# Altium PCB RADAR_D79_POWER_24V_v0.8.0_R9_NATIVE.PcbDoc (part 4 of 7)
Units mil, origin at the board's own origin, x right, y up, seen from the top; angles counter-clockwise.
Board outline 3110.24 x 3110.24 mil, 8 copper layers (Top Layer, GND1, SIG1, PWR1, PWR2, SIG2, GND2, Bottom Layer), stack 55.2 mil thick; 304 components, 269 nets, 1408 pads, 1366 vias.

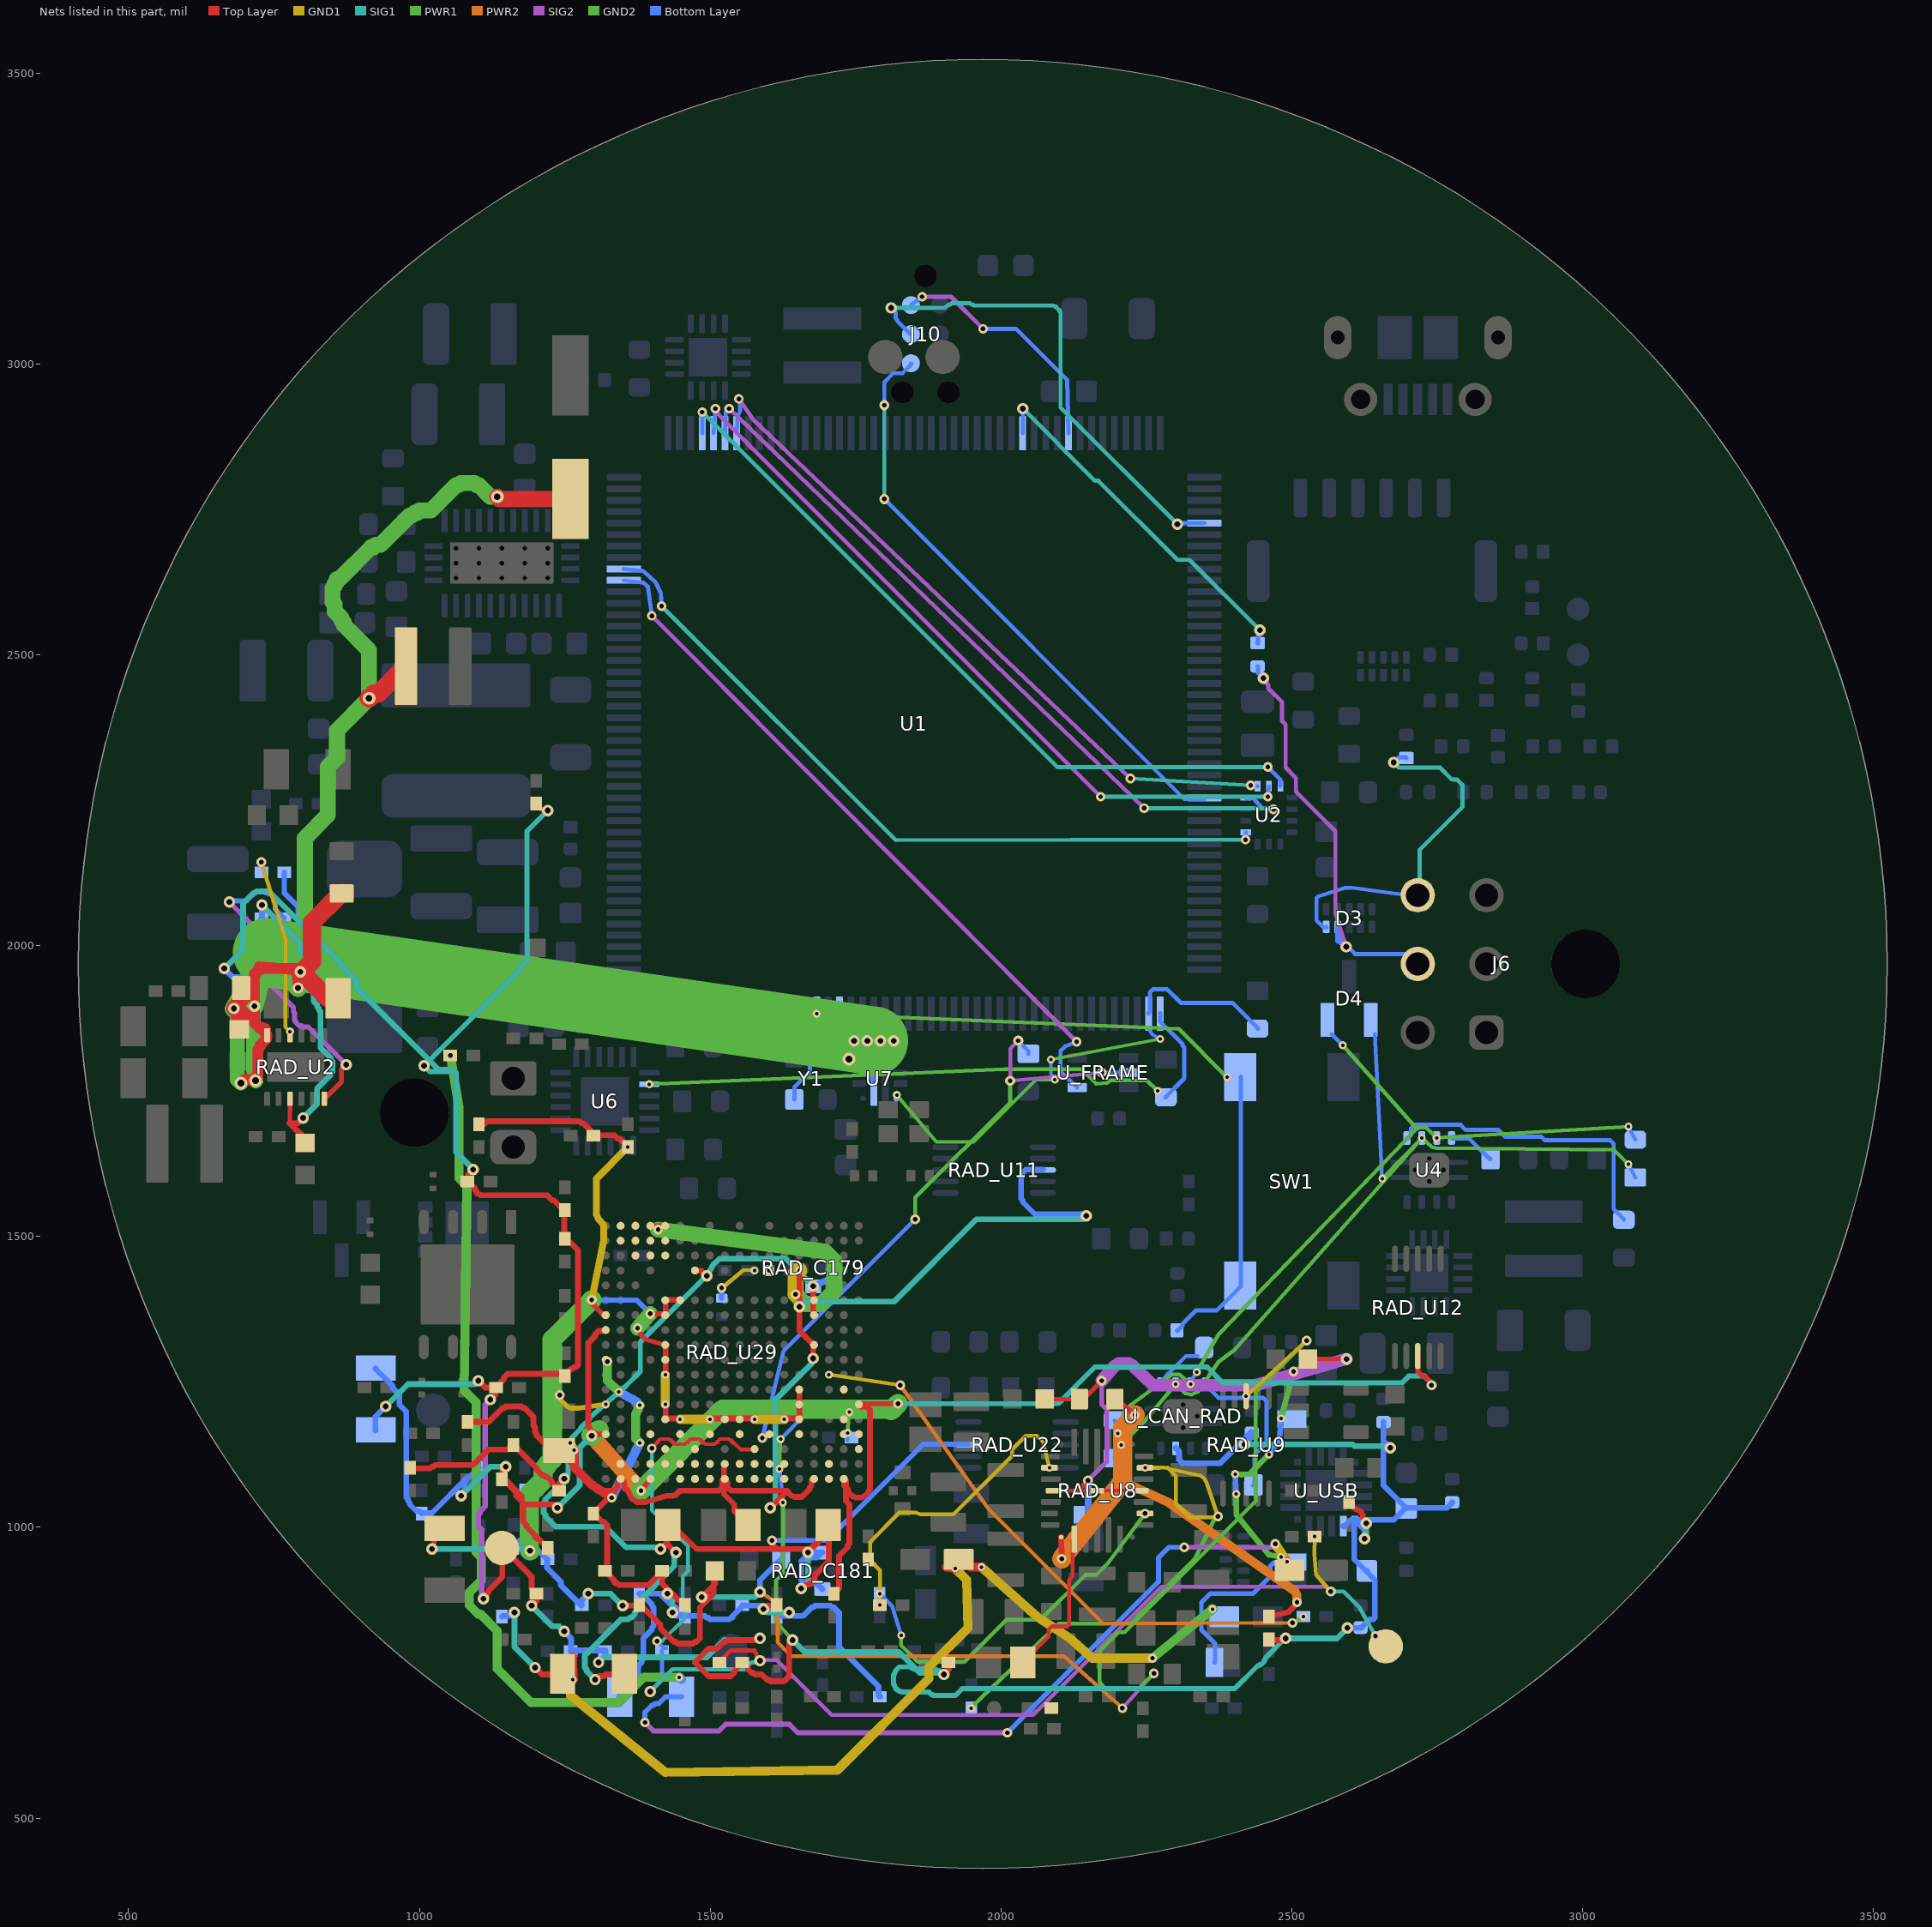
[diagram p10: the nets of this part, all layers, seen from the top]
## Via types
v1: diameter 13.77, hole 5.9, Top Layer to GND1, tented both sides, 393 vias
v2: diameter 16.54, hole 7.87, Top Layer to Bottom Layer, tented both sides, 129 vias
v3: diameter 13.77/13.77 (per signal layer), hole 5.9, Top Layer to GND1, tented both sides, 120 vias
v4: diameter 13.77, hole 5.9, Top Layer to GND1, tented top, 104 vias
v5: diameter 19.68, hole 9.84, Top Layer to Bottom Layer, 103 vias
v6: diameter 19.68, hole 9.84, Top Layer to Bottom Layer, tented both sides, 93 vias
v7: diameter 13.78, hole 5.91, Top Layer to GND1, tented both sides, 83 vias
v8: diameter 17.32, hole 7.87, Top Layer to Bottom Layer, tented both sides, 69 vias
v9: diameter 13.78, hole 5.91, GND2 to Bottom Layer, tented both sides, 68 vias
v10: diameter 13.78, hole 5.91, Top Layer to GND1, tented bottom, 55 vias
v11: diameter 13.78, hole 5.91, GND2 to Bottom Layer, tented top, 43 vias
v12: diameter 16.54, hole 7.87, GND2 to Bottom Layer, tented both sides, 22 vias
v13: diameter 22.05, hole 11.81, Top Layer to Bottom Layer, tented both sides, 17 vias
v14: diameter 16.54, hole 7.87, Top Layer to Bottom Layer, 14 vias
v15: diameter 18.11, hole 9.06, Top Layer to Bottom Layer, 7 vias
v16: diameter 22.83, hole 11.81, Top Layer to Bottom Layer, 6 vias
v17: diameter 22.05, hole 11.81, Top Layer to Bottom Layer, 6 vias
v18: diameter 22.83, hole 11.81, Top Layer to Bottom Layer, tented both sides, 5 vias
v19: diameter 19.68, hole 7.87, Top Layer to Bottom Layer, 3 vias
v20: diameter 17.32, hole 8.66, Top Layer to Bottom Layer, 3 vias
v21: diameter 20.47, hole 9.84, Top Layer to Bottom Layer, 3 vias
v22: diameter 17.72, hole 9.84, Top Layer to Bottom Layer, tented both sides, 2 vias
v23: diameter 22.05, hole 11.02, Top Layer to Bottom Layer, 2 vias
v24: diameter 19.68, hole 11.81, Top Layer to Bottom Layer, 2 vias
v25: diameter 19.68, hole 9.84, SIG1 to Bottom Layer, 2 vias
v26: diameter 16.54, hole 7.87, SIG1 to SIG2, tented both sides, 2 vias
v27: diameter 16.54, hole 7.87, Top Layer to SIG1, 2 vias
v28: diameter 13.78, hole 5.91, Top Layer to GND1, 2 vias
v29: diameter 18, hole 9.84, Top Layer to Bottom Layer, tented both sides, 1 vias
v30: diameter 18.11, hole 9.06, Top Layer to Bottom Layer, tented both sides, 1 vias
v31: diameter 19.68, hole 9.84, GND2 to Bottom Layer, tented both sides, 1 vias
v32: diameter 17.32, hole 7.87, SIG1 to Bottom Layer, tented both sides, 1 vias
v33: diameter 19.68, hole 9.84, SIG2 to Bottom Layer, 1 vias
v34: diameter 16.54, hole 7.87, GND1 to PWR2, tented both sides, 1 vias

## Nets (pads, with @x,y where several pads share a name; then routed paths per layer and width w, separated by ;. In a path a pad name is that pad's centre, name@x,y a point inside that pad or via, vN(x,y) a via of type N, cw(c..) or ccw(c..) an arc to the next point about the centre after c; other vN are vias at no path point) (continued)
HOST_UART2_RX_EXT: D3.5 J6.6 R604.1 | length 624.9
  SIG1 w7.09: v5(2675.2,2314.96) 2684.06,2306.1 2754.92,2306.1 2775.59,2285.43 2784.45,2285.43 2793.31,2276.57 2793.31,2238.19 2719.49,2164.37 2719.49,2090.55 2716.54,2087.6 J6.6@2716.54,2086.61
  Bottom Layer w7.09: D3.5@2559.06,2032.09 2560.04,2031.5 2554.13,2031.5 2542.32,2043.31 2542.32,2081.69 2545.28,2084.65 2591.54,2099.41 2604.33,2099.41 2713.58,2084.65 2716.54,2087.6 J6.6@2716.54,2086.61 ; v5(2675.2,2314.96) 2684.06,2323.82 2695.87,2323.82 R604.1@2696.85,2322.44
HOST_UART2_TX: R603.2 U1.120 | length 634.1
  SIG1 w7.09: v6(2037.4,2923.23) 2161.42,2799.21 2167.32,2799.21 2303.15,2663.39 2323.82,2663.39 v5(2444.88,2542.32)
  Bottom Layer w7.09: U1.120@2037.4,2880.91 2037.4,2881.89 v6(2037.4,2923.23) ; R603.2@2440.94,2520.08 2441.93,2518.7 2441.93,2539.37 v5(2444.88,2542.32)
HOST_UART2_TX_EXT: D3.4 J6.5 R603.1 | length 758.4
  SIG2 w7.09: v5(2450.79,2459.65) 2456.69,2453.74 2456.69,2450.79 2459.65,2447.83 2459.65,2441.93 2483.27,2418.31 2483.27,2385.83 2489.17,2379.92 2489.17,2306.1 2506.89,2288.39 2506.89,2264.76 2574.8,2196.85 2574.8,2055.12 v33(2593.5,1998.03)
  Bottom Layer w7.09: R603.1@2440.94,2479.92 2441.93,2480.32 2441.93,2468.5 v5(2450.79,2459.65) ; D3.4@2578.74,2032.09 D3.4@2577.76,2031.5 ; v33(2593.5,1998.03) 2577.76,2007.87 D3.4@2577.76,2031.5 ; J6.5@2716.54,1968.5 2715.94,1969.09 2699.41,1985.63 2608.46,1985.63 2580.91,2013.19 2580.71,2013.78 2580.71,2028.54 D3.4@2577.76,2031.5
IMU_DRDY: U1.80 U2.4 | length 1289
  SIG1 w7.09: v2(1416.34,2583.66) 1818.9,2181.1 v2(2420.28,2182.09)
  Bottom Layer w7.09: U1.80@1351.38,2647.64 1381.89,2644.68 1386.81,2642.72 1406.5,2624.02 1415.35,2605.32 v2(1416.34,2583.66) ; v2(2420.28,2182.09) U2.4@2420.77,2194.88
IMU_MISO: U1.94 U2.1 | length 1314.4
  SIG1 w7.09: v26(2246.06,2236.22) 2466.54,2236.22 v2(2468.5,2234.25)
  SIG2 w7.09: v2(1532.48,2923.23) v26(2246.06,2236.22)
  Bottom Layer w7.09: U1.94@1525.59,2880.91 1526.57,2917.32 v2(1532.48,2923.23) ; U2.1@2420.77,2253.94 2433.07,2253.94 2448.82,2236.22 v2(2468.5,2234.25)
IMU_MOSI: U1.95 U2.14 | length 1218.4
  SIG1 w7.09: v26(2222.44,2287.4) v2(2429.13,2275.59)
  SIG2 w7.09: v2(1549.21,2939.96) 1574.8,2903.54 v26(2222.44,2287.4)
  Bottom Layer w7.09: U1.95@1545.28,2880.91 1547.24,2911.42 1550.2,2915.35 1551.18,2918.31 1551.18,2937.99 v2(1549.21,2939.96) ; v2(2429.13,2275.59) U2.14@2440.94,2274.11
IMU_NSS: U1.92 U2.12 | length 1303.6
  SIG1 w7.09: v2(1486.22,2917.32) 2096.46,2307.09 v2(2458.66,2307.09)
  Bottom Layer w7.09: U1.92@1486.22,2880.91 v2(1486.22,2917.32) ; v2(2458.66,2307.09) 2480.32,2285.43 U2.12@2480.31,2274.11
IMU_SCK: U1.93 U2.13 | length 1289
  SIG1 w7.09: v2(2171.26,2255.91) v2(2458.66,2255.91)
  SIG2 w7.09: v2(1508.86,2923.23) 1513.78,2913.39 v2(2171.26,2255.91)
  Bottom Layer w7.09: U1.93@1505.91,2880.91 v2(1508.86,2923.23) ; v2(2458.66,2255.91) U2.13@2460.63,2274.11
MCU_HSE_25M: U1.29 Y1.3 | length 204.3
  Bottom Layer w7.09: Y1.3@1644.68,1735.24 1644.68,1736.22 1644.68,1756.89 1668.31,1780.51 1671.26,1780.51 1671.26,1830.71 1683.07,1842.52 1718.5,1842.52 1718.5,1845.47 1721.46,1848.43 1721.46,1883.86 U1.29@1722.44,1882.87
NRST: C115.1 SW1.1 U1.31 | length 1247.5
  GND2 w6.69: v11(1683.07,1882.87) 2305.51,1856.69 v11(2388.58,1773.62)
  Bottom Layer w7.09: C115.1@2302.36,1338.58 2303.15,1337.6 2312.01,1346.46 2312.01,1349.41 2335.63,1373.03 2371.06,1373.03 SW1.1@2412.4,1414.37 ; SW1.1@2411.42,1415.35 SW1.1@2412.4,1414.37 ; SW1.1@2411.42,1773.62 2412.4,1774.61 SW1.1@2412.4,1414.37
RAD_CAN_SHDN: R_CAN_SHDN.1 U_CAN_RAD.5 | length 81.7
  Bottom Layer w6.3: U_CAN_RAD.5@2276.18,1253.35 2276.08,1253.69 2277.31,1253.69 2285.93,1262.3 2285.93,1263.53 2287.16,1263.53 2287.16,1264.76 2288.39,1264.76 2288.39,1265.99 2289.62,1265.99 2317.91,1294.29 2337.6,1294.29 R_CAN_SHDN.1@2338.19,1294.88
RAD_CAN_STB: R_CAN_STB.1 U_CAN_RAD.8 | length 275.4
  Bottom Layer w7.09: U_CAN_RAD.8@2351.38,1246.06 2350.39,1246.06 2374.02,1222.44 2450.79,1222.44 2456.69,1216.54 2456.69,1145.67 2436.02,1125 2436.02,1074.8 2433.07,1071.85 R_CAN_STB.1@2434.06,1072.83
RAD_FRAME_RAW: R_FRAME_PD.1 RAD_U29.G15 U_FRAME.2 | length 1106.1
  Top Layer w7.09: v2(1589.57,1153.54) 1590.55,1154.53 1595.47,1154.53 1601.38,1160.43 RAD_U29.G15@1601.8,1160.03
  PWR1 w7.09: v2(1852.36,1529.53) 1852.36,1566.93 2015.75,1730.32 v8(2015.75,1767.72)
  SIG2 w6.69: v8(2015.75,1767.72) 2015.75,1822.83 v8(2029.53,1836.61)
  SIG2 w7.09: v8(2015.75,1767.72) v2(2173.03,1781.69)
  Bottom Layer w6.69: v8(2029.53,1836.61) 2047.24,1818.9 2047.24,1812.99 R_FRAME_PD.1@2047.24,1813.98
  Bottom Layer w7.09: v2(1589.57,1153.54) 1625.98,1303.15 v2(1852.36,1529.53) ; v2(2173.03,1781.69) U_FRAME.2@2219.49,1781.5
RADAR_12V: RAD_C99.1 RAD_C101.1 RAD_C118.2 RAD_C173.2 RAD_C195.1 RAD_L5.2 RAD_R7.1 RAD_U2.12 U7.6 | length 4804.6
  Top Layer w12.2: v6(716.54,1895.67) 716.54,1897.64 716.54,1870.08 740.16,1846.46 RAD_U2.12@737.32,1846.42
  Top Layer w18.9: v6(681.1,1891.73) 682.09,1890.75 692.91,1890.75 727.36,1856.3 RAD_U2.12@735.24,1856.3 ; v13(692.91,1763.78) 698.82,1769.68 710.63,1769.68 712.6,1770.47 716.54,1770.47 720.47,1775.59 721.42,1779.53 722.44,1781.5 722.44,1820.87 ; v6(716.54,1895.67) 716.54,1870.08 718.5,1868.11 718.5,1866.14 ; v13(718.5,1767.72) 722.44,1771.65 722.44,1820.87 ; RAD_U2.12@734.84,1856.69 RAD_U2.12@735.24,1856.3 ; RAD_U2.12@737.32,1846.42 RAD_U2.12@737.32,1846.82 ; v6(791.34,1927.17) 791.34,1946.85 790.55,1948.82 790.55,1952.76 785.43,1956.69 783.8,1957.03 781.83,1959 724.71,1963.68 724.08,1957.03 722.44,1956.69 718.5,1952.76 717.56,1948.82 716.54,1946.85 716.54,1872.05 717.56,1870.08 718.5,1866.14 ; v6(795.28,1954.72) 789.37,1960.63 729.33,1960.63 728.35,1959.65 725.39,1959.65 724.41,1958.66 723.43,1958.66 717.52,1952.76 717.52,1951.77 716.54,1950.79 716.54,1947.83 715.55,1946.85 715.55,1872.05 716.54,1871.06 716.54,1868.11 717.52,1867.13 717.52,1866.14 723.43,1860.24 724.41,1860.24 725.39,1859.25 728.35,1859.25 729.33,1858.27 733.27,1858.27 RAD_U2.12@735.24,1856.3 ; 718.5,1866.14 RAD_U2.12@737.32,1846.82 ; 722.44,1820.87 724.41,1822.83 724.41,1824.8 726.38,1826.77 726.38,1828.74 737.32,1840.91 RAD_U2.12@737.32,1846.82
  Top Layer w25.59: v6(681.1,1891.73) v6@681.1,1893.7 ; RAD_C195.1@690.2,1856.13 688.98,1854.33 688.98,1885.83 v6@681.1,1893.7 ; RAD_C118.2@693.77,1927.05 692.91,1925.2 692.91,1905.51 v6@681.1,1893.7
  Top Layer w27.56: v23(1133.86,2771.65) 1137.8,2767.72 RAD_C99.1@1259.84,2767.72
  Top Layer w31.5: v6(795.28,1954.72) v6@796.18,1952.76 ; RAD_C101.1@860.24,1909.45 858.27,1909.45 842.52,1909.45 799.21,1952.76 v6@796.18,1952.76 ; RAD_C173.2@866.14,2089.57 866.14,2090.55 814.96,2039.37 814.96,1972.44 v6@796.18,1952.76 ; v23(913.39,2425.2) 921.26,2433.07 929.13,2433.07 976.38,2480.32 RAD_L5.2@976.97,2480.32
  PWR1 w25.59: v6(681.1,1891.73) 683.07,1889.76 683.07,1885.83 687.01,1881.89 687.01,1769.68 v13(692.91,1763.78) ; v6(716.54,1895.67) 714.57,1893.7 714.57,1785.43 716.54,1783.46 716.54,1777.56 718.5,1775.59 v13(718.5,1767.72) ; v17(1738.19,1805.12) 1738.19,1826.77 1748.03,1836.61 v6(1747.24,1836.22)
  PWR1 w27.56: v6(795.28,1954.72) 795.28,1952.76 795.28,1968.5 803.15,1976.38 803.15,2185.04 842.52,2224.41 842.52,2307.09 858.27,2322.83 858.27,2370.08 v23(913.39,2425.2) 913.39,2507.87 870.08,2551.18 870.08,2555.12 866.14,2559.06 866.14,2562.99 854.33,2574.8 854.33,2586.61 850.39,2590.55 850.39,2614.17 854.33,2618.11 854.33,2622.05 858.27,2625.98 858.27,2629.92 862.2,2629.92 917.32,2685.04 921.26,2685.04 925.2,2688.98 933.07,2688.98 984.25,2740.16 988.19,2740.16 992.13,2744.09 996.06,2744.09 1000,2748.03 1019.68,2748.03 1062.99,2791.34 1066.93,2791.34 1070.87,2795.28 1094.49,2795.28 1098.43,2791.34 1102.36,2791.34 1122.05,2771.65 v23(1133.86,2771.65)
  PWR1 w31.5: v6(681.1,1891.73) 738.19,1988.19 ; v6(716.54,1895.67) 738.19,1988.19 ; v6(791.34,1927.17) 738.19,1988.19 ; v6(795.28,1954.72) 738.19,1988.19
  PWR1 w39.37: v6(1747.24,1836.22) 1781.5,1836.22 ; v6(1770.08,1836.22) 1781.5,1836.22 ; v6(1792.91,1836.22) 1781.5,1836.22 ; v6(1815.75,1836.22) 1781.5,1836.22
  PWR1 w118.11: 738.19,1988.19 1781.5,1836.22
  Bottom Layer w9.45: RAD_R7.1@767.72,2125.98 767.72,2090.55 791.34,2066.93 791.34,1956.69 795.28,1952.76 v6(795.28,1954.72)
  Bottom Layer w10.24: U7.6@1781.5,1807.87 1781.5,1836.22
  Bottom Layer w15.75: v17(1738.19,1805.12) 1744.09,1811.02 1744.09,1814.96 1746.06,1816.93 1746.06,1818.9 1750,1822.83 1751.97,1822.83 1753.94,1824.8 1771.65,1824.8 ; v6(1747.24,1836.22) 1748.03,1836.61 1759.84,1824.8 1771.65,1824.8 ; v6(1770.08,1836.22) 1769.68,1836.61 1781.5,1824.8 ; v6(1792.91,1836.22) 1793.31,1836.61 1781.5,1824.8 ; v6(1815.75,1836.22) 1814.96,1836.61 1811.02,1832.68 1791.34,1832.68 1789.37,1832.09 1787.4,1832.09 1783.46,1826.77 1783.13,1825.14 1781.5,1822.83 U7.6@1781.5,1771.65 ; 1771.65,1824.8 1773.62,1822.83 1775.59,1822.83 1779.53,1818.9 1779.53,1816.93 1781.5,1814.96 U7.6@1781.5,1771.65 ; U7.6@1781.5,1771.65 1781.5,1824.8
  Bottom Layer w18.5: v6(1747.24,1836.22) v6(1815.75,1836.22)
RADAR_CANH: D4.1 R40.1 R_CAN_TERM.1 U4.7 U_CAN_RAD.7 | length 1404.4
  GND2 w6.69: v9(2200.79,1161.42) 2212.6,1200.79 2216.54,1205.71 2294.29,1262.8 2306.1,1262.8 2308.07,1261.81 v11(2325.79,1246.06) ; v9(2336.61,1266.73) 2375,1332.68 2714.57,1685.04 ; v9(2587.6,1828.74) 2714.57,1685.04 ; v9(3078.74,1688.98) v11(2749.02,1669.29) 2731.3,1687.01 2721.46,1687.01 2714.57,1685.04
  Bottom Layer w6.69: R_CAN_TERM.1@2194.88,1184.06 v9(2200.79,1161.42) ; U_CAN_RAD.7@2327.17,1253.15 v9(2336.61,1266.73) ; D4.1@2568.11,1848.23 v9(2587.6,1828.74) ; v9(3078.74,1688.98) R40.1@3090.55,1666.34
RADAR_CANL: D4.2 R40.2 R_CAN_TERM.2 U4.6 U_CAN_RAD.6 | length 1538.3
  GND2 w6.69: v9(2206.69,1141.73) 2244.09,1179.13 v11(2300.2,1246.06) 2316.93,1230.32 2327.76,1228.35 2337.6,1232.28 2374.02,1284.45 2400.59,1304.13 v11(2723.43,1669.29) ; v9(2655.51,1599.41) v11(2723.43,1669.29) ; v9(3078.74,1624.02) 3054.13,1648.62 2748.03,1651.57 2741.14,1653.54 v11(2723.43,1669.29)
  Bottom Layer w6.69: R_CAN_TERM.2@2194.88,1119.09 v9(2206.69,1141.73) ; D4.2@2642.91,1848.23 v9(2655.51,1599.41) ; v9(3078.74,1624.02) R40.2@3090.55,1601.38
RADAR_EFUSE_FLT: R7F.1 U1.2 U7.4 | length 871.5
  GND2 w6: v9(1820.87,1743.11) 1888.78,1662.4 1952.76,1662.4 2060.04,1769.68 v9(2092.52,1769.68) ; v9(2085.63,1804.13) v9(2273.62,1839.57)
  Bottom Layer w6: U7.4@1820.08,1737.4 v9(1820.87,1743.11) ; v9(2085.63,1804.13) 2085.63,1780.51 v9(2092.52,1769.68) ; U1.2@2252.76,1858.07 2259.84,1847.44 v9(2273.62,1839.57)
  Bottom Layer w7.09: U1.2@2253.94,1882.87 2252.95,1883.86 2255.91,1886.81 2255.91,1919.29 2261.81,1925.2 2285.43,1925.2 2309.06,1901.57 2397.64,1901.57 2441.93,1857.28 R7F.1@2440.94,1857.28
RADAR_REF: U1.79 U_FRAME.4 | length 1236.5
  SIG2 w7.09: v2(1399.61,2566.93) v2(2129.92,1834.65)
  Bottom Layer w7.09: U1.79@1351.38,2627.95 1384.84,2624.02 1392.72,2617.13 v2(1399.61,2566.93) ; v2(2129.92,1834.65) 2110.24,1826.77 2102.36,1818.9 2102.36,1783.46 U_FRAME.4@2130.91,1755.91
SHDN_PD: R42.1 U4.5 | length 525.9
  Bottom Layer w7.09: U4.5@2697.83,1669.29 2698.82,1668.31 2704.72,1674.21 2704.72,1686.02 2707.68,1688.98 2707.68,1691.93 2790.35,1691.93 2799.21,1683.07 2855.32,1683.07 2867.13,1671.26 2929.13,1671.26 2935.04,1665.35 3047.24,1665.35 3053.15,1659.45 3053.15,1547.24 3070.87,1529.53 R42.1@3070.87,1528.54
STB_PD: R41.1 U4.8 | length 82.4
  Bottom Layer w7.09: U4.8@2774.61,1669.29 2775.59,1668.31 2805.12,1668.31 2840.55,1632.87 R41.1@2841.54,1633.86
SWCLK: J10.4 U1.137 | length 856.4
  SIG1 w7.09: v6(1811.02,3096.46) 1903.54,3096.46 1907.48,3100.39 1909.45,3100.39 1911.42,3102.36 1913.39,3102.36 1915.35,3104.33 1946.85,3104.33 1948.82,3102.36 1950.79,3102.36 1952.76,3100.39 2090.55,3100.39 2092.52,3098.43 2094.49,3098.43 2100.39,3092.52 2100.39,3090.55 2102.36,3088.58 2102.36,2925.2 v6(2303.15,2724.41)
  Bottom Layer w7.09: v6(1811.02,3096.46) 1818.9,3088.58 1818.9,3078.74 1820.87,3076.77 1820.87,3074.8 1844.49,3051.18 J10.4@1845.08,3051.18 ; v6(2303.15,2724.41) 2305.12,2726.38 2348.43,2726.38 U1.137@2349.41,2726.38
SWDIO: J10.2 U1.124 | length 424.2
  SIG2 w7.09: v2(1864.37,3115.55) 1913.98,3115.55 v2(1969.09,3060.43)
  Bottom Layer w7.09: J10.2@1845.08,3101.18 v2(1864.37,3115.55) ; v2(1969.09,3060.43) 2025.59,3060.43 2113.78,2972.24 U1.124@2116.14,2880.91
SWO: J10.6 U1.161 | length 1029.9
  SIG1 w6.69: v8(1799.21,2767.72) v8(1799.21,2929.13)
  Bottom Layer w6.69: v8(1799.21,2767.72) 2314.96,2251.97 2350.39,2251.97 U1.161@2349.41,2253.94 ; v8(1799.21,2929.13) 1799.21,2968.5 1814.96,2984.25 1830.71,2984.25 1846.46,3000 J10.6@1845.08,3001.18
SYS_EFUSE_FLT: R6F.1 U1.1 U6.14 | length 1071.9
  GND2 w6.69: v11(1395.18,1761.61) 2006.3,1787.4 2138.58,1787.4 2163.78,1762.2 2182.68,1763.78 2187.4,1768.5 2250.39,1768.5 v11(2269.49,1750.2)
  Bottom Layer w7.09: U1.1@2273.62,1882.87 2273.62,1883.86 2273.62,1869.09 2312.01,1830.71 2312.01,1827.76 2314.96,1824.8 2314.96,1771.65 2282.48,1739.17 R6F.1@2283.46,1739.17
TI_1V0: RAD_C114.1 RAD_C115.2 RAD_C116.1 RAD_C117.2 RAD_C179.1 RAD_C179.3 RAD_C181.1 RAD_C181.3 RAD_R56.1 RAD_R64.2 RAD_U22.8 RAD_U29.D6 RAD_U29.D7 RAD_U29.M4 | length 3150.8
  Top Layer w8.66: v8(1606.3,977.36) 1606.3,971.46 1615.16,962.6 1671.26,962.6 1703.74,995.08 RAD_C114.1@1703.74,1003.94
  Top Layer w9.84: RAD_R56.1@984.25,1102.36 983.27,1101.38 1018.7,1101.38 1021.65,1104.33 1024.61,1104.33 1027.56,1107.28 1092.52,1107.28 1119.09,1133.86 1151.57,1133.86 RAD_C117.2@1160.43,1142.72 ; RAD_C117.2@1161.42,1141.73 RAD_C117.2@1160.43,1142.72 ; v5(1249.02,1083.66) 1240.16,1074.8 RAD_C115.2@1240.16,1062.99 1228.35,1074.8 1228.35,1077.76 1219.49,1086.61 1216.54,1086.61 1213.58,1089.57 1210.63,1089.57 1201.77,1098.43 1201.77,1101.38 RAD_C117.2@1160.43,1142.72 ; v5(1302.17,738.19) 1308.07,744.09 1316.93,744.09 1319.88,747.05 1352.36,747.05 RAD_R64.2@1352.36,748.03 ; v6(1414.37,962.6) 1426.18,974.41 RAD_C116.1@1426.18,1003.94 ; RAD_C116.1@1427.17,1003.94 RAD_C116.1@1426.18,1003.94 ; v5(1440.94,956.69) 1426.18,971.46 RAD_C116.1@1426.18,1003.94 ; RAD_U29.M4@1473.85,1441.52 1473.43,1440.94 1485.24,1440.94 v6(1494.09,1432.09) ; v5(1656.5,894.68) 1662.4,900.59 1668.31,900.59 1671.26,903.54 1674.21,903.54 1677.17,906.5 1677.17,909.45 1680.12,912.4 1680.12,918.31 1703.74,941.93 RAD_C114.1@1703.74,1003.94 ; v6(1677.17,1414.37) RAD_U29.D6@1677.17,1390.75 ; RAD_U29.D7@1678.57,1364.75 1677.17,1364.17 RAD_U29.D6@1677.17,1390.75 ; RAD_U29.D6@1678.57,1390.34 RAD_U29.D6@1677.17,1390.75 ; RAD_C114.1@1702.76,1003.94 RAD_C114.1@1703.74,1003.94 ; RAD_C116.1@1426.18,1003.94 1435.04,1003.94 1476.38,962.6 1671.26,962.6 1674.21,965.55 1677.17,965.55 1700.79,989.17 1700.79,1000.98 RAD_C114.1@1703.74,1003.94
  SIG1 w8.66: v5(1249.02,1083.66) 1250,1082.68 1253.94,1086.61 1253.94,1088.58 1255.91,1090.55 1255.91,1141.73 1261.81,1147.64 1261.81,1153.54 1277.56,1169.29 1277.56,1171.26 1293.31,1187.01 1293.31,1188.98 1355.32,1243.11 1379.92,1267.72 1379.92,1275.59 1379.92,1318.9 1494.09,1433.07 v6(1494.09,1432.09)
  SIG1 w9.84: v5(1249.02,1083.66) 1249.02,1080.71 1216.54,1048.23 1216.54,1045.28 1213.58,1042.32 1213.58,1024.61 1216.54,1021.65 1216.54,1018.7 1234.25,1000.98 1319.88,1000.98 1355.32,965.55 1411.42,965.55 v6(1414.37,962.6) ; v5(1302.17,738.19) 1287.4,752.95 1287.4,755.91 1284.45,758.86 1284.45,779.53 1346.46,841.54 1358.27,841.54 1361.22,844.49 1364.17,844.49 1370.08,850.39 1370.08,853.35 1373.03,856.3 1373.03,868.11 1437.99,933.07 1437.99,953.74 v5(1440.94,956.69) ; v6(1494.09,1432.09) 1504.92,1450.79 1515.75,1461.61 1629.92,1461.61 1659.45,1432.09 v6(1677.17,1414.37) ; v5(1656.5,894.68) 1668.31,906.5 v5(1668.31,956.69)
  Bottom Layer w8.66: v8(1606.3,977.36) 1700.79,977.36 1866.14,1142.72 1942.91,1142.72 RAD_U22.8@1943.9,1141.73
  Bottom Layer w9.84: v5(1668.31,956.69) RAD_C181.1@1691.93,956.69 ; RAD_C181.3@1692.91,893.7 1691.93,894.68 1683.07,903.54 1662.4,903.54 1656.5,909.45 1656.5,941.93 1659.45,944.88 1662.4,944.88 1665.35,947.83 1683.07,947.83 RAD_C181.1@1691.93,956.69 ; RAD_C181.1@1692.91,956.69 RAD_C181.1@1691.93,956.69
  Bottom Layer w11.81: v6(1677.17,1414.37) 1705.22,1426.67 1711.12,1431.59 1713.09,1436.02 1713.09,1455.71 1712.11,1458.17 1707.18,1464.07 RAD_C179.3@1677.17,1477.36
TI_1V0_FILTERED: RAD_R64.1 RAD_R66.1 RAD_R73.2 RAD_R111.2 | length 1726.6
  Top Layer w9.84: v5(1198.82,758.86) 1210.63,747.05 1246.06,747.05 RAD_R64.1@1246.06,748.03
  Top Layer w15.75: RAD_R64.1@1262.99,777.76 v10(1263.78,738.19) ; RAD_R111.2@1906.3,931.5 v10(1921.26,929.13) ; RAD_R111.2@1948.03,931.5 v7(1966.54,931.59)
  GND1 w15.75: v10(1263.78,738.19) 1259.84,734.25 1259.84,710.63 1423.23,578.74 1718.5,582.68 1875.98,740.16 1875.98,759.84 1942.91,826.77 1940.94,909.45 v10(1921.26,929.13) ; v7(1966.54,931.59) 2062.5,845.96 2118.6,809.06 2156.99,775.1 v2(2260.33,775.1)
  SIG1 w9.84: v5(1163.39,853.35) 1163.39,794.29 v5(1198.82,758.86)
  GND2 w15.75: v2(2260.33,775.1) v11(2363.68,859.25)
  Bottom Layer w9.84: RAD_R66.1@1141.73,846.46 1142.72,847.44 1157.48,847.44 v5(1163.39,853.35)
  Bottom Layer w15.75: RAD_R73.2@2362.99,859.84 v11(2363.68,859.25)
TI_1V2: RAD_C92.2 RAD_C96.2 RAD_C137.2 RAD_C138.2 RAD_C139.2 RAD_C140.2 RAD_C141.2 RAD_C142.2 RAD_C146.2 RAD_R26.1 RAD_R30.2 RAD_U9.8 RAD_U29.E12 RAD_U29.E13 RAD_U29.E14 RAD_U29.F14 RAD_U29.H14 RAD_U29.J14 RAD_U29.K14 RAD_U29.L14 RAD_U29.N6 RAD_U29.N14 RAD_U29.P6 RAD_U29.P7 RAD_U29.P9 RAD_U29.P10 RAD_U29.P11 RAD_U29.P13 RAD_U29.P14 RAD_U29.V7 RAD_U29.V13 | length 4865
  Top Layer w7.87: v2(1375,1342.52) 1380.91,1330.71 1388.78,1322.83 RAD_U29.P9@1422.67,1313.57
  Top Layer w8.66: v8(1296.26,1390.75) 1296.26,1384.84 1316.93,1364.17 1319.88,1364.17 RAD_U29.V7@1320.3,1364.75 ; v8(1396.65,1367.13) 1420.28,1367.13 1423.23,1364.17 RAD_U29.P7@1422.67,1364.75
  Top Layer w9.84: v6(1021.65,962.6) 1024.61,965.55 1024.61,980.32 1042.32,998.03 RAD_R30.2@1043.31,998.03 ; RAD_R26.1@1102.36,1692.91 1101.38,1691.93 1110.24,1691.93 1116.14,1697.83 1275.59,1697.83 1278.54,1694.88 1281.5,1694.88 1296.26,1680.12 1296.26,1677.17 RAD_C139.2@1299.21,1674.21 ; RAD_C139.2@1299.21,1673.23 RAD_C139.2@1299.21,1674.21 ; v5(1349.41,865.16) RAD_C96.2@1378.94,865.16 ; v10(1358.27,1653.54) 1343.5,1668.31 1340.55,1668.31 1334.65,1674.21 RAD_C139.2@1299.21,1674.21 ; RAD_C96.2@1377.95,866.14 RAD_C96.2@1378.94,865.16 ; RAD_U29.P14@1422.67,1185.62 RAD_U29.P14@1423.23,1187.01 ; v10(1422.67,1211.21) 1423.23,1210.63 RAD_U29.P14@1423.23,1187.01 ; v10(1422.67,1262.39) 1423.23,1263.78 RAD_U29.P10@1423.23,1287.4 ; RAD_U29.P10@1422.67,1287.98 RAD_U29.P10@1423.23,1287.4 ; RAD_U29.P9@1422.67,1313.57 1423.23,1313.98 RAD_U29.P10@1423.23,1287.4 ; RAD_U29.P7@1422.67,1364.75 1423.23,1364.17 RAD_U29.P6@1423.23,1390.75 ; RAD_U29.P6@1422.67,1390.34 RAD_U29.P6@1423.23,1390.75 ; v10(1448.26,1185.62) 1446.85,1187.01 RAD_U29.P14@1423.23,1187.01 ; RAD_U29.N6@1448.26,1390.34 1446.85,1390.75 RAD_U29.P6@1423.23,1390.75 ; v5(1485.24,879.92) 1508.86,903.54 RAD_C146.2@1508.86,924.21 ; v10(1499.44,1185.62) 1500,1187.01 RAD_U29.K14@1523.62,1187.01 ; RAD_C146.2@1507.87,925.2 RAD_C146.2@1508.86,924.21 ; RAD_U29.K14@1525.03,1185.62 RAD_U29.K14@1523.62,1187.01 ; RAD_U29.J14@1550.62,1185.62 RAD_U29.J14@1550.2,1187.01 ; v10(1576.21,1185.62) 1576.77,1187.01 RAD_U29.J14@1550.2,1187.01 ; v10(1627.39,1185.62) 1626.97,1187.01 RAD_U29.E14@1653.54,1187.01 ; RAD_U29.E14@1652.98,1185.62 RAD_U29.E14@1653.54,1187.01 ; RAD_U29.E13@1652.98,1211.21 RAD_U29.E13@1653.54,1210.63 ; RAD_U29.E12@1652.98,1236.8 1653.54,1237.2 RAD_U29.E13@1653.54,1210.63 ; RAD_C96.2@1378.94,865.16 1381.89,865.16 1414.37,832.68 1414.37,826.77 1437.99,803.15 1440.94,803.15 1443.9,800.2 1470.47,800.2 1473.43,803.15 1476.38,803.15 1482.28,809.06 1482.28,862.2 1505.91,885.83 1505.91,921.26 RAD_C146.2@1508.86,924.21 ; RAD_U29.K14@1523.62,1187.01 RAD_U29.J14@1550.2,1187.01 ; RAD_U29.E14@1653.54,1187.01 RAD_U29.E13@1653.54,1210.63
  PWR1 w6.69: v2(2262.8,749.02) 2237.2,723.43 2179.13,723.43 2169.29,733.27 2169.29,787.4 2201.77,819.88 2212.6,819.88 2437.99,1045.28 2437.99,1233.27 v2(2525.59,1320.87)
  PWR1 w15.75: 1228.35,1219.49 v14(1241.14,1227.36)
  PWR1 w25.59: v2(1375,1342.52) v8(1396.65,1367.13)
  PWR1 w33.46: v5(1189.96,959.65) 1188.98,960.63 1188.98,1057.09 1212.6,1080.71 1212.6,1098.43 1218.5,1104.33 1218.5,1106.3 1228.35,1116.14 1228.35,1322.83 1295.28,1389.76 v8(1296.26,1390.75)
  PWR2 w6.69: v5(1585.63,888.78) 1601.38,878.94 1616.14,864.17 1616.14,802.17 1639.76,778.54 2108.27,778.54 v2(2208.66,688.98)
  GND1 w6.69: v7(2421.26,1225.39) v2(2525.59,1320.87)
  GND1 w8.66: v14(1241.14,1227.36) 1242.13,1219.49 1253.94,1207.68 1259.84,1204.72 1273.62,1204.72 v10(1320.3,1211.21)
  GND1 w11.81: v8(1296.26,1390.75) 1316.93,1493.11 1316.93,1519.68 1308.07,1529.53 1304.13,1537.4 1304.13,1599.41 v10(1358.27,1653.54)
  GND1 w15.75: v10(1422.67,1211.21) v10(1422.67,1262.39) ; v10(1448.26,1185.62) v10(1499.44,1185.62) ; v10(1576.21,1185.62) v10(1627.39,1185.62)
  SIG1 w9.84: v6(1021.65,962.6) 1187.01,962.6 v5(1189.96,959.65) ; v5(1290.35,885.83) 1328.74,885.83 v5(1349.41,865.16) ; v5(1485.24,879.92) 1576.77,879.92 v5(1585.63,888.78)
  SIG2 w6.69: v2(2208.66,688.98) v2(2262.8,749.02)
  Bottom Layer w8.66: v8(1296.26,1390.75) 1373.03,1390.75 v8(1396.65,1367.13)
  Bottom Layer w9.84: RAD_C92.2@1161.42,964.57 RAD_C92.2@1160.43,965.55 ; RAD_C141.2@1181.1,1062.99 1184.06,1060.04 1184.06,983.27 1181.1,980.32 1178.15,980.32 1175.2,977.36 1172.24,977.36 RAD_C92.2@1160.43,965.55 ; v5(1189.96,959.65) 1184.06,965.55 RAD_C92.2@1160.43,965.55 ; RAD_C138.2@1220.47,944.88 RAD_C138.2@1219.49,944.88 ; RAD_C140.2@1279.53,866.14 RAD_C140.2@1278.54,865.16 ; v5(1290.35,885.83) 1278.54,874.02 RAD_C140.2@1278.54,865.16 ; v5(1585.63,888.78) 1585.63,909.45 1621.06,944.88 RAD_C137.2@1622.05,944.88 ; RAD_C92.2@1160.43,965.55 1198.82,965.55 RAD_C138.2@1219.49,944.88 ; RAD_C138.2@1219.49,944.88 1219.49,930.12 1243.11,906.5 1243.11,900.59 RAD_C140.2@1278.54,865.16
TI_1V4_APLL: RAD_C103.1 RAD_U29.H4 | length 85.1
  GND1 w7.48: v2(1519.68,1411.42) 1557.09,1441.93 v10(1576.21,1441.52)
  Bottom Layer w8.66: RAD_C103.1@1519.69,1393.7 v2(1519.68,1411.42)
TI_1V4_SYNTH: RAD_C102.1 RAD_U29.G4
  other v14: 1601.8,1441.52
TI_1V8: RAD_C5.2 RAD_C107.2 RAD_C110.1 RAD_C111.2 RAD_C112.1 RAD_C113.2 RAD_C163.2 RAD_C164.2 RAD_C165.2 RAD_C168.2 RAD_C170.2 RAD_C172.2 RAD_R47.1 RAD_R60.2 RAD_U11.8 RAD_U29.D9 RAD_U29.D18 RAD_U29.E4 RAD_U29.K17 RAD_U29.K18 RAD_U29.P1 RAD_U29.R1 RAD_U29.U18 RAD_U29.V10 | length 4518.8
  Top Layer w9.84: RAD_C5.2@1082.68,1181.1 1083.66,1181.1 1119.09,1181.1 1142.72,1204.72 1145.67,1204.72 1148.62,1207.68 1175.2,1207.68 1178.15,1204.72 1181.1,1204.72 1195.87,1189.96 1195.87,1175.2 1198.82,1172.24 1198.82,1163.39 1201.77,1160.43 1201.77,1157.48 1225.39,1133.86 1237.2,1133.86 RAD_C112.1@1240.16,1130.91 ; RAD_C112.1@1240.16,1131.89 RAD_C112.1@1240.16,1130.91 ; RAD_C111.2@1299.21,1023.62 RAD_C111.2@1299.21,1024.61 ; RAD_C165.2@1318.9,925.2 RAD_C165.2@1319.88,924.21 ; RAD_U29.U18@1345.89,1083.26 RAD_U29.U18@1346.46,1083.66 ; RAD_U29.R1@1397.08,1518.3 1396.65,1517.72 1423.23,1517.72 RAD_U29.P1@1422.67,1518.3 v2(1410.43,1511.81) ; RAD_C107.2@1417.32,925.2 RAD_C107.2@1417.32,924.21 ; v5(1426.18,885.83) 1429.13,882.87 1437.99,882.87 RAD_C168.2@1455.71,865.16 ; RAD_C168.2@1456.69,866.14 RAD_C168.2@1455.71,865.16 ; RAD_U29.K18@1525.03,1083.26 RAD_U29.K18@1523.62,1083.66 ; RAD_U29.K17@1525.03,1108.85 1523.62,1110.24 RAD_U29.K18@1523.62,1083.66 ; RAD_C110.1@1564.96,1003.94 1541.34,1027.56 1541.34,1039.37 1523.62,1057.09 RAD_U29.K18@1523.62,1083.66 ; v6(1591.54,859.25) 1597.44,865.16 1615.16,865.16 RAD_C163.2@1614.17,866.14 ; v5(1603.35,1033.46) 1632.87,1062.99 ; v10(1652.98,1441.52) RAD_U29.E4@1653.54,1440.94 ; v5(1653.54,1378.94) RAD_U29.E4@1653.54,1440.94 ; v6(1677.17,1290.35) RAD_U29.D9@1677.17,1313.98 ; RAD_U29.D18@1678.57,1083.26 1677.17,1083.66 1674.21,1080.71 1674.21,1071.85 1671.26,1068.9 1671.26,1065.94 1668.31,1062.99 1657.48,1052.17 1644.68,1052.17 1639.76,1054.13 1632.87,1061.02 1632.87,1062.99 ; RAD_U29.D9@1678.57,1313.57 RAD_U29.D9@1677.17,1313.98 ; RAD_C112.1@1240.16,1130.91 1299.21,1071.85 1299.21,1068.9 1305.12,1062.99 1334.65,1062.99 ; RAD_C111.2@1299.21,1024.61 1334.65,1060.04 1334.65,1062.99 ; RAD_C111.2@1299.21,1024.61 1313.98,1009.84 1316.93,1009.84 1322.83,1003.94 1322.83,927.17 RAD_C165.2@1319.88,924.21 ; RAD_C165.2@1319.88,924.21 1334.65,909.45 1334.65,906.5 1337.6,903.54 1340.55,903.54 1343.5,900.59 1393.7,900.59 RAD_C107.2@1417.32,924.21 ; 1334.65,1062.99 1340.55,1068.9 1340.55,1077.76 RAD_U29.U18@1346.46,1083.66 ; RAD_U29.U18@1346.46,1083.66 1352.36,1077.76 1352.36,1065.94 1355.32,1065.94 1358.27,1062.99 1365.16,1049.21 1374.02,1043.31 1388.78,1043.31 1425.2,1054.13 1435.04,1054.13 1439.96,1055.12 1447.83,1062.99 1514.76,1062.99 1520.67,1068.9 1520.67,1080.71 RAD_U29.K18@1523.62,1083.66 ; RAD_C107.2@1417.32,924.21 1417.32,903.54 RAD_C168.2@1455.71,865.16 ; RAD_U29.K18@1523.62,1083.66 1529.53,1077.76 1529.53,1068.9 1535.43,1062.99 1632.87,1062.99 ; RAD_U29.E4@1653.54,1440.94 1653.54,1337.6 RAD_U29.D9@1677.17,1313.98
  Top Layer w15.75: v7(1266.24,1132.38) 1266.24,1102.85 1296.75,1072.34 1297.74,1072.34 v2(1330.71,1050.69)
  GND1 w15.75: v7(1259.01,1144.88) v7(1266.24,1132.38)
  GND1 w27.56: v2(1646.65,1400.59) 1646.65,1436.02 v10(1652.98,1441.52)
  SIG1 w9.84: v5(1426.18,885.83) 1435.04,876.97 v5(1435.04,853.35) ; v6(1591.54,859.25) 1597.44,853.35 v5(1635.83,853.35) ; v5(1603.35,1033.46) 1612.2,1042.32 1612.2,1219.49 1674.21,1281.5 1674.21,1287.4 v6(1677.17,1290.35) ; v5(1653.54,1378.94) 1662.4,1387.8 1815.94,1387.8 1957.68,1529.53 2140.75,1529.53 v5(2146.65,1535.43)
  GND2 w15.75: v14(1323.26,1285.03) 1323.33,1252.46 v9(1343.01,1232.78) ; v9(1378.94,1145.18) 1371.56,1152.56 1371.56,1192.91 v9(1378.94,1209.65)
  GND2 w27.56: v2(1410.43,1511.81) 1696.85,1474.41 1713.58,1457.68 1713.58,1406.5 1690.94,1383.86 1663.39,1383.86 v2(1646.65,1400.59)
  Bottom Layer w9.84: RAD_R60.2@1344.49,708.66 1343.5,708.66 1375.98,741.14 1375.98,761.81 1381.89,767.72 1381.89,770.67 1384.84,773.62 1384.84,809.06 1399.61,823.82 1399.61,826.77 1402.56,829.72 1402.56,862.2 1399.61,865.16 1399.61,868.11 1384.84,882.87 1381.89,882.87 RAD_C113.2@1378.94,885.83 ; RAD_C113.2@1377.95,885.83 RAD_C113.2@1378.94,885.83 ; v5(1435.04,853.35) 1440.94,847.44 RAD_C172.2@1455.71,847.44 ; RAD_C172.2@1456.69,846.46 RAD_C172.2@1455.71,847.44 ; RAD_C164.2@1555.12,866.14 RAD_C164.2@1556.1,865.16 ; RAD_C170.2@1614.17,846.46 RAD_C170.2@1615.16,847.44 ; v5(1635.83,853.35) 1629.92,847.44 RAD_C170.2@1615.16,847.44 ; RAD_R47.1@1791.34,708.66 1792.32,708.66 1789.37,711.61 1789.37,726.38 1721.46,794.29 1721.46,853.35 1712.6,862.2 1709.65,862.2 1706.69,865.16 1680.12,865.16 1677.17,862.2 1674.21,862.2 1659.45,847.44 RAD_C170.2@1615.16,847.44 ; RAD_U11.8@2071.85,1614.17 2072.83,1615.16 2043.31,1615.16 2037.4,1609.25 2037.4,1606.3 2034.45,1603.35 2034.45,1564.96 2037.4,1562.01 2037.4,1559.06 2058.07,1538.39 2143.7,1538.39 v5(2146.65,1535.43) ; RAD_C113.2@1378.94,885.83 1414.37,885.83 1437.99,862.2 1440.94,862.2 RAD_C172.2@1455.71,847.44 ; RAD_C172.2@1455.71,847.44 1491.14,847.44 1494.09,844.49 1497.05,844.49 1500,841.54 1532.48,841.54 1535.43,844.49 1538.39,844.49 1538.39,847.44 RAD_C164.2@1556.1,865.16 ; RAD_C164.2@1556.1,865.16 1591.54,865.16 1594.49,862.2 1597.44,862.2 1600.39,859.25 1603.35,859.25 RAD_C170.2@1615.16,847.44
  Bottom Layer w15.75: v2(1330.71,1050.69) v9(1378.94,1145.18) ; v9(1343.01,1232.78) 1373.03,1216.04 v9(1378.94,1209.65)
TI_1V8_FILTERED: RAD_R60.1 RAD_R65.1 RAD_R104.2 | length 2868
  Top Layer w15.75: v10(2492.13,940.94) RAD_R104.2@2496.06,926.18
  GND1 w15.75: v2(2471.46,971.46) v10(2492.13,940.94)
  SIG2 w8.66: v2(1387.8,664.37) 1402.56,649.61 1514.76,649.61 1526.57,661.42 1635.83,661.42 1650.59,646.65 v2(2010.83,646.65) ; v2(2314.96,965.55) 2465.55,965.55 v2(2471.46,971.46)
  GND2 w15.75: v14(1053.15,1811.02) 1067.91,1721.46 1067.91,1600.39 1081.69,1586.61 1076.77,1235.24 1097.44,1214.57 1097.44,956.69 1106.3,947.83 1106.3,908.46 1085.63,887.8 1085.63,866.14 1101.38,850.39 1105.32,850.39 1133.86,821.85 1133.86,756.89 1191.93,698.82 1342.52,698.82 1385.83,742.13 v11(1446.85,742.13)
  Bottom Layer w8.66: v2(1387.8,664.37) 1387.8,682.09 1399.61,693.9 1402.56,693.9 1405.51,696.85 1411.42,696.85 1423.23,708.66 1449.8,708.66 RAD_R60.1@1450.79,708.66 ; v2(2010.83,646.65) 2270.67,906.5 2270.67,947.83 2288.39,965.55 v2(2314.96,965.55)
  Bottom Layer w15.75: v11(1446.85,742.13) RAD_R60.1@1450.79,738.39
TI_3V3: RAD_C174.2 RAD_C175.2 RAD_C176.2 RAD_C177.2 RAD_R346.2 RAD_R348.1 RAD_U12.8 RAD_U29.A13 RAD_U29.B18 RAD_U29.R18 RAD_U29.V8 RAD_U29.V15 | length 3488.3
  Top Layer w8.66: RAD_U29.A13@1755.34,1211.21 1755.91,1212.6 v8(1822.83,1212.6) ; RAD_U12.8@2716.54,1294.29 2716.54,1295.28 2716.54,1267.72 2724.41,1259.84 2728.35,1259.84 2736.22,1251.97 2736.22,1248.03 v8(2740.16,1244.09)
  Top Layer w9.84: RAD_C174.2@1141.73,1082.68 RAD_C174.2@1142.72,1083.66 ; v5(1148.62,1104.33) 1142.72,1098.43 RAD_C174.2@1142.72,1083.66 ; RAD_C176.2@1220.47,964.57 1219.49,965.55 1204.72,980.32 1201.77,980.32 1198.82,983.27 1198.82,986.22 1184.06,1000.98 1184.06,1003.94 1178.15,1009.84 1178.15,1042.32 1166.34,1054.13 1166.34,1060.04 1163.39,1062.99 1163.39,1065.94 1160.43,1065.94 RAD_C174.2@1142.72,1083.66 ; v5(1237.2,1033.46) 1231.3,1039.37 1181.1,1039.37 1175.2,1045.28 1175.2,1054.13 1145.67,1083.66 RAD_C174.2@1142.72,1083.66 ; v6(1296.26,1157.48) 1299.21,1160.43 RAD_U29.V15@1319.88,1160.43 ; RAD_U29.V15@1320.3,1160.03 RAD_U29.V15@1319.88,1160.43 ; RAD_U29.V8@1320.3,1339.16 1319.88,1340.55 1316.93,1337.6 1308.07,1337.6 1302.17,1331.69 1302.17,1328.74 1299.21,1325.79 1290.35,1316.93 1290.35,1300.2 1290.35,1174.21 1294.29,1166.34 1304.13,1160.43 RAD_U29.V15@1319.88,1160.43 ; v2(1380.91,1062.99) RAD_U29.R18@1397.08,1083.26 ; RAD_C175.2@1712.6,885.83 1721.46,894.68 1721.46,950.79 1736.22,965.55 1736.22,968.5 1739.17,971.46 1739.17,1039.37 1733.27,1045.28 1733.27,1080.71 RAD_U29.B18@1730.32,1083.66 ; RAD_U29.B18@1729.75,1083.26 RAD_U29.B18@1730.32,1083.66 ; RAD_U29.A13@1755.34,1211.21 1753.94,1210.63 1756.89,1207.68 1768.7,1207.68 1774.61,1201.77 1774.61,1065.94 1769.68,1057.09 1759.84,1051.18 1750,1051.18 1745.08,1053.15 1738.19,1060.04 1736.22,1065.94 1730.32,1071.85 RAD_U29.B18@1730.32,1083.66
  PWR1 w33.46: v6(1296.26,1157.48) 1295.28,1157.48 1303.15,1165.35 1307.09,1165.35 1309.06,1167.32 ; v2(1380.91,1062.99) 1521.26,1203.15 1812.6,1203.15 v8(1822.83,1212.6) 1811.02,1200.79
  PWR2 w27.56: v6(1296.26,1157.48) v2(1380.91,1062.99)
  SIG1 w8.66: v8(1822.83,1212.6) 2098.43,1212.6 2161.42,1275.59 2354.33,1275.59 2381.89,1248.03 2688.98,1248.03 2700.79,1259.84 2728.35,1259.84 2740.16,1248.03 v8(2740.16,1244.09)
  SIG1 w9.84: v5(1071.85,1054.13) 1122.05,1104.33 v5(1148.62,1104.33) ; v5(1237.2,1033.46) 1275.59,1071.85 1275.59,1136.81 v6(1296.26,1157.48)
  Bottom Layer w9.84: RAD_R346.2@925.2,1273.62 924.21,1272.64 953.74,1243.11 953.74,1240.16 965.55,1228.35 965.55,1210.63 977.36,1198.82 977.36,1051.18 980.32,1048.23 980.32,1045.28 983.27,1042.32 983.27,1039.37 995.08,1027.56 1000.98,1027.56 RAD_R348.1@1003.94,1024.61 ; RAD_R348.1@1003.94,1023.62 RAD_R348.1@1003.94,1024.61 ; v5(1071.85,1054.13) 1077.76,1060.04 1077.76,1077.76 1080.71,1080.71 1080.71,1083.66 1083.66,1086.61 ; RAD_C177.2@1102.36,1102.36 1101.38,1101.38 1086.61,1086.61 1083.66,1086.61 ; RAD_R348.1@1003.94,1024.61 1021.65,1024.61 1083.66,1086.61
TI_3V3_VIO: C_CAN_RAD.1 C_USB_1U.1 C_USB_4U7.1 C_USB_100N.1 R_USB_RESET.1 R_USB_WAKE.1 RAD_R37.1 RAD_R38.2 RAD_R41.2 RAD_R43.2 RAD_R49.2 RAD_R106.2 RAD_R116.2 RAD_R264.2 RAD_R276.2 RAD_R277.2 RAD_R301.2 RAD_R309.2 RAD_R311.2 RAD_R346.1 RAD_R352.1 RAD_R409.2 TP_RAD_VIO.1 U_CAN_RAD.3 U_USB.6 U_USB.7 | length 7052.8
  Top Layer w8.66: RAD_R276.2@1200.79,2244.09 1212.6,2232.28 v6(1220.47,2232.28)
  Top Layer w9.84: RAD_R38.2@1082.68,1594.49 RAD_R38.2@1083.66,1594.49 ; v5(1092.52,1615.16) 1083.66,1606.3 RAD_R38.2@1083.66,1594.49 ; v5(1101.38,1251.97) 1113.19,1240.16 RAD_R41.2@1130.91,1240.16 ; v5(1110.24,876.97) 1116.14,882.87 1116.14,885.83 1119.09,888.78 1119.09,891.73 1142.72,915.35 TP_RAD_VIO.1@1142.72,965.55 ; v5(1122.05,1219.49) 1130.91,1228.35 RAD_R41.2@1130.91,1240.16 ; RAD_R41.2@1131.89,1240.16 RAD_R41.2@1130.91,1240.16 ; TP_RAD_VIO.1@1141.73,964.57 TP_RAD_VIO.1@1142.72,965.55 ; v5(1192.91,865.16) 1201.77,874.02 RAD_R311.2@1201.77,885.83 ; RAD_R311.2@1200.79,885.83 RAD_R311.2@1201.77,885.83 ; RAD_R43.2@1250,1259.84 RAD_R43.2@1249.02,1260.83 ; RAD_R37.1@1250,1496.06 RAD_R37.1@1249.02,1497.05 ; RAD_R49.2@1250,1545.28 RAD_R49.2@1249.02,1544.29 ; RAD_R264.2@1555.12,767.72 RAD_R264.2@1556.1,767.72 ; v5(1585.63,809.06) 1582.68,806.1 1529.53,806.1 1526.57,803.15 1523.62,803.15 1511.81,791.34 1497.05,791.34 1473.43,767.72 1497.05,744.09 1535.43,744.09 1541.34,750 1541.34,752.95 RAD_R264.2@1556.1,767.72 ; v5(1641.73,806.1) 1635.83,800.2 1635.83,744.09 1626.97,735.24 1603.35,735.24 1600.39,738.19 1597.44,738.19 1588.58,747.05 1576.77,747.05 1573.82,750 1570.87,750 1564.96,755.91 1564.96,758.86 RAD_R264.2@1556.1,767.72 ; v5(1901.57,747.05) 1910.43,755.91 1910.43,767.72 RAD_R106.2@1909.45,767.72 ; RAD_R116.2@2460.63,807.09 2459.65,806.1 2486.22,806.1 v5(2489.17,809.06) ; RAD_R409.2@2598.43,1043.31 2598.43,1042.32 2610.24,1030.51 2613.19,1030.51 2616.14,1027.56 2619.09,1027.56 2619.09,1024.61 2622.05,1021.65 2622.05,1015.75 2627.95,1009.84 v6(2627.95,1006.89) ; RAD_R38.2@1083.66,1594.49 1095.47,1582.68 1095.47,1579.72 1098.43,1576.77 1098.43,1573.82 1101.38,1573.82 1104.33,1570.87 1219.49,1570.87 1228.35,1562.01 1231.3,1562.01 RAD_R49.2@1249.02,1544.29 ; RAD_R41.2@1130.91,1240.16 1145.67,1254.92 1145.67,1257.87 1151.57,1263.78 1246.06,1263.78 RAD_R43.2@1249.02,1260.83 ; TP_RAD_VIO.1@1142.72,965.55 1192.91,915.35 1192.91,894.68 RAD_R311.2@1201.77,885.83 ; RAD_R43.2@1249.02,1260.83 1260.83,1272.64 1263.78,1272.64 1266.73,1275.59 1269.68,1275.59 1272.64,1278.54 1272.64,1476.38 1254.92,1494.09 1251.97,1494.09 RAD_R37.1@1249.02,1497.05 ; RAD_R37.1@1249.02,1497.05 RAD_R49.2@1249.02,1544.29
  SIG1 w8.66: 1060.04,1783.46 1059.06,1783.46 1017.72,1783.46 v6(1007.87,1793.31) 1173.23,1958.66 1173.23,1962.6 1185.04,1974.41 1185.04,2196.85 v6(1220.47,2232.28) ; v5(1901.57,747.05) 1901.57,746.06 1893.7,753.94 1889.76,753.94 1887.8,755.91 1850.39,755.91 1848.43,757.87 1846.46,757.87 1844.49,759.84 1824.8,759.84 1818.9,753.94 1818.9,751.97 1816.93,750 1816.93,748.03 1814.96,746.06 1814.96,730.32 1816.93,728.35 1816.93,726.38 1818.9,724.41 1818.9,722.44 1820.87,720.47 1822.83,720.47 1824.8,718.5 1826.77,718.5 1828.74,716.54 1875.98,716.54 1879.92,712.6 1881.89,712.6 1883.86,710.63 1921.26,710.63 1933.07,722.44 2401.57,722.44 2440.94,761.81 2442.91,761.81 2444.88,763.78 2446.85,763.78 2452.76,769.68 2452.76,771.65 2454.72,773.62 2454.72,775.59 2488.19,809.06 v5(2489.17,809.06)
  SIG1 w9.84: v5(664.37,1960.63) 696.85,1993.11 696.85,2072.83 714.57,2090.55 717.52,2090.55 720.47,2093.5 738.19,2093.5 741.14,2090.55 744.09,2090.55 865.16,1969.49 865.16,1966.54 891.73,1939.96 891.73,1928.15 1033.46,1786.42 1054.13,1786.42 1057.09,1783.46 1060.04,1783.46 1062.99,1780.51 1062.99,1644.68 v5(1092.52,1615.16) ; v5(941.93,1207.68) 980.32,1246.06 1095.47,1246.06 v5(1101.38,1251.97) ; v5(1192.91,865.16) 1228.35,829.72 1240.16,829.72 v5(1249.02,820.87) ; v5(1308.07,767.72) 1316.93,776.57 1494.09,776.57 1523.62,806.1 1582.68,806.1 v5(1585.63,809.06) ; v5(1641.73,806.1) 1662.4,785.43 1824.8,785.43 1860.24,750 1898.62,750 v5(1901.57,747.05) ; v5(2418.31,1142.72) 2604.33,1142.72 2607.28,1139.76 2666.34,1139.76 v5(2669.29,1136.81) ; v5(2489.17,809.06) 2577.76,809.06 v5(2595.47,826.77) ; v5(2625,980.32) 2627.95,983.27 v6(2627.95,1006.89)
  SIG2 w9.84: v5(1110.24,876.97) 1107.28,879.92 1107.28,995.08 1101.38,1000.98 1101.38,1021.65 1104.33,1024.61 1104.33,1027.56 1113.19,1036.42 1113.19,1210.63 v5(1122.05,1219.49)
  GND2 w6.69: v9(1619.09,1100.39) 1619.09,1123.03 v9(1621.06,1151.57) ; v9(1625,1042.32) 1625,920.28 1613.19,908.46 1613.19,837.6 v5(1641.73,806.1) ; v11(1736.22,1162.4) v9(1739.17,1197.83)
  Bottom Layer w6.69: v9(1619.09,1100.39) v9(1625,1042.32) ; v9(1621.06,1151.57) 1663.39,1193.9 v9(1739.17,1197.83) ; RAD_R309.2@1736.02,1149.41 v11(1736.22,1162.4)
  Bottom Layer w9.84: v5(664.37,1960.63) 679.13,1945.87 750,1945.87 752.95,1948.82 752.95,1954.72 767.72,1969.49 RAD_R277.2@767.72,1968.5 ; RAD_R346.1@925.2,1167.32 924.21,1166.34 924.21,1189.96 v5(941.93,1207.68) ; v5(1249.02,820.87) 1260.83,809.06 RAD_R352.1@1260.83,788.39 ; RAD_R352.1@1259.84,787.4 RAD_R352.1@1260.83,788.39 ; v5(1308.07,767.72) 1319.88,779.53 RAD_R301.2@1319.88,788.39 ; RAD_R301.2@1318.9,787.4 RAD_R301.2@1319.88,788.39 ; U_CAN_RAD.3@2300.2,1135.83 2300.2,1136.81 2306.1,1130.91 2306.1,1116.14 2312.01,1110.24 2376.97,1110.24 C_CAN_RAD.1@2430.12,1163.39 ; v5(2418.31,1142.72) 2430.12,1154.53 C_CAN_RAD.1@2430.12,1163.39 ; C_CAN_RAD.1@2431.1,1162.2 C_CAN_RAD.1@2430.12,1163.39 ; U_USB.7@2588.58,1001.97 2589.57,1000.98 2601.38,1012.8 U_USB.6@2607.28,1012.8 ; v5(2595.47,826.77) C_USB_100N.1@2619.09,826.77 ; U_USB.6@2608.27,1013.78 U_USB.6@2607.28,1012.8 ; C_USB_100N.1@2618.11,827.56 C_USB_100N.1@2619.09,826.77 ; v5(2625,980.32) 2625,995.08 U_USB.6@2607.28,1012.8 ; C_USB_4U7.1@2628.94,925.2 C_USB_4U7.1@2627.95,924.21 ; R_USB_RESET.1@2657.48,1180.71 R_USB_RESET.1@2657.48,1181.1 ; v5(2669.29,1136.81) 2657.48,1148.62 R_USB_RESET.1@2657.48,1181.1 ; C_USB_1U.1@2696.85,1032.48 C_USB_1U.1@2695.87,1033.46 ; R_USB_WAKE.1@2775.59,1042.91 2775.59,1042.32 2766.73,1033.46 C_USB_1U.1@2695.87,1033.46 ; RAD_R352.1@1260.83,788.39 RAD_R301.2@1319.88,788.39 ; U_USB.6@2607.28,1012.8 2675.2,1012.8 C_USB_1U.1@2695.87,1033.46 ; U_USB.6@2607.28,1012.8 2607.28,944.88 C_USB_4U7.1@2627.95,924.21 ; C_USB_100N.1@2619.09,826.77 2633.86,841.54 2639.76,841.54 2642.72,844.49 2642.72,909.45 C_USB_4U7.1@2627.95,924.21 ; R_USB_RESET.1@2657.48,1181.1 2657.48,1071.85 C_USB_1U.1@2695.87,1033.46
TI_3V3REG_ENA: RAD_R7.2 RAD_U2.10 | length 326
  Top Layer w6.69: RAD_U2.10@777.36,1853.54 v10(777.56,1852.36)
  GND1 w6.69: v2(728.35,2143.7) 769.68,2011.81 769.68,1860.24 v10(777.56,1852.36)
  Bottom Layer w6.69: v2(728.35,2143.7) RAD_R7.2@735.43,2120.87
TI_3V3REG_MODE: RAD_R9.1 RAD_U2.6 | length 576.7
  Top Layer w8.66: RAD_U2.6@836.61,1736.61 836.61,1736.22 866.14,1765.75 866.14,1787.4 v6(874.02,1795.28)
  SIG2 w8.66: v6(673.23,2074.8) 708.66,2039.37 708.66,2027.56 710.63,2025.59 710.63,1966.54 783.46,1893.7 783.46,1885.83 785.43,1883.86 785.43,1872.05 787.4,1870.08 787.4,1868.11 793.31,1862.2 797.24,1862.2 799.21,1860.24 809.06,1860.24 v6(874.02,1795.28)
  Bottom Layer w8.66: v6(673.23,2074.8) 675.2,2076.77 702.76,2076.77 718.5,2092.52 734.25,2092.52 736.22,2090.55 740.16,2090.55 742.13,2088.58 744.09,2088.58 748.03,2084.65 748.03,2082.68 750,2080.71 750,2076.77 751.97,2074.8 751.97,2062.99 RAD_R9.1@767.72,2047.24
TI_3V3REG_VCC: RAD_C10.1 RAD_R9.2 RAD_U2.3 | length 570
  Top Layer w8: 777.47,1694.53 777.25,1694.75 777.25,1715.25 777.56,1715.25 RAD_U2.3@777.56,1736.61
  Top Layer w9.84: 777.47,1694.53 776.57,1694.88 791.34,1694.88 v5(800.2,1703.74)
  Top Layer w10: 777.47,1694.75 777.47,1694.53 RAD_C10.1@803.56,1668.44
  SIG1 w9.84: v6(729.33,2069.88) 794.29,2004.92 794.29,1990.16 817.91,1966.54 817.91,1904.53 823.82,1898.62 823.82,1895.67 826.77,1892.72 826.77,1889.76 829.72,1886.81 829.72,1824.8 847.44,1807.09 847.44,1804.13 850.39,1801.18 850.39,1783.46 847.44,1780.51 847.44,1777.56 823.82,1753.94 823.82,1727.36 v5(800.2,1703.74)
  Bottom Layer w9.84: RAD_R9.2@728.35,2047.24 729.33,2046.26 v6(729.33,2069.88)
TI_5V0: RAD_C119.1 RAD_U8.10 | length 265.3
  Top Layer w7.09: RAD_C119.1@2037.4,767.72 2081.69,812.01 2081.69,823.82 2087.6,829.72 2114.17,829.72 2117.13,832.68 2117.13,909.45 2123.03,915.35 2123.03,977.36 2125.98,980.32 RAD_U8.10@2125.98,979.82
TI_+3.3VD: RAD_C124.2 RAD_R116.1 RAD_U8.9 | length 802
  Top Layer w9.84: RAD_U8.9@2103.41,983.08 v2(2104.33,945.87) ; RAD_C124.2@2195.87,1220.47 v2(2230.32,1192.91) ; RAD_R116.1@2460.63,846.46 2494.09,854.33 2502.95,863.19 v2(2508.86,871.06)
  PWR2 w15.75: 2209.25,1078.94 2288.19,1042.52 2505.51,889.76 2508.66,883.46 v2(2508.86,871.06)
  PWR2 w33.46: v2(2104.33,945.87) 2209.25,1078.94 2209.25,1171.06 v2(2230.32,1192.91)
TI_AGND: RAD_C3.1 RAD_C123.1 RAD_C124.1 RAD_NT1.2 RAD_NT2.1 RAD_NT3.1 RAD_NT4.1 RAD_U8.5 RAD_U8.5-19 RAD_U8.19 | length 1816.1
  Top Layer w7.09: RAD_C123.1@2074.8,1220.47 RAD_C124.1@2134.84,1220.47 ; RAD_U8.5@2088.58,1062.99 RAD_U8.5-19@2165.35,1062.99 RAD_U8.19@2242.13,1062.99 ; RAD_C3.1@2527.56,1289.37 v5(2594,1289.37)
  Top Layer w7.87: 2126.97,1062.99 2125.98,1062.99 2131.89,1062.99 v8(2149.61,1080.71) ; RAD_C124.1@2134.84,1220.47 2134.84,1219.49 2140.75,1219.49 v8(2173.23,1251.97)
  SIG2 w7.87: v8(2149.61,1080.71) 2182.09,1113.19 2182.09,1201.77 2173.23,1210.63 v8(2173.23,1251.97)
  SIG2 w9.84: 2468.88,1253.31 v2(2502.95,1267.72)
  SIG2 w21.65: v8(2173.23,1251.97) 2195.08,1277.36 2201.97,1281.5 2219.88,1281.5 2225.39,1278.74 2261.22,1244.29 2437.6,1244.29 v5(2594,1289.37)
  GND2 w9.84: v9(2402.56,1091.54) 2412.4,1090.55 2427.17,1091.54 v9(2460.63,1125) ; v9(2404.53,1057.09) 2404.53,1021.65 2460.63,952.76 v11(2481.3,948.9) ; v11(2481.3,1187.01) v2(2502.95,1267.72)
  Bottom Layer w7.09: RAD_NT1.2@2496,940.2 2498,940.2 RAD_NT1.2@2500,940.2
  Bottom Layer w7.87: RAD_NT4.1@2366.89,767.72 2368.11,767.72 2368.11,800.2 2344.49,823.82 2344.49,871.06 2359.25,885.83 2433.07,885.83 2462.6,915.35 2462.6,933.07 2468.5,938.98 2495.08,938.98 RAD_NT1.2@2496,940.2
  Bottom Layer w9.84: v9(2402.56,1091.54) v9(2404.53,1057.09) ; v9(2460.63,1125) 2478.35,1148.62 2481.3,1177.09 v11(2481.3,1187.01)
  Bottom Layer w11.81: RAD_NT3.1@2149.61,1021.65 v8(2149.61,1080.71)
TI_AR_NERROUT: RAD_R76.1 RAD_U29.C11 | length 1010.9
  PWR2 w6.69: v2(1826.77,1244.09) 1978.35,1031.5 2175.2,834.65 v2(2500.98,835.63)
  GND1 w6.69: v10(1704.16,1262.39) v2(1826.77,1244.09)
  GND2 w6.69: v2(2500.98,835.63) v11(2519.69,846.46)
TI_AR_NRST: RAD_C105.2 RAD_R99.1 RAD_R264.1 RAD_U29.H16 TP_RAD_RESET.1 | length 2378.5
  Top Layer w6.3: v2(1399.61,1135.63) 1406.69,1142.72 1406.69,1144.49 1408.46,1144.49 1408.46,1146.26 1410.24,1146.26 1410.24,1148.03 1412.01,1148.03 1412.01,1149.8 1413.78,1151.57 1429.72,1151.57 1431.5,1149.8 1433.27,1149.8 1433.27,1148.03 1435.04,1148.03 1435.04,1146.26 1436.81,1146.26 1436.81,1144.49 1438.58,1144.49 1440.35,1142.72 1456.3,1142.72 1459.84,1146.26 1461.61,1146.26 1461.61,1148.03 1463.39,1148.03 1463.39,1149.8 1465.16,1151.57 1481.1,1151.57 1482.87,1149.8 1484.65,1149.8 1484.65,1148.03 1486.42,1148.03 1486.42,1146.26 1488.19,1146.26 1488.19,1144.49 1489.96,1144.49 1491.73,1142.72 1507.68,1142.72 1511.22,1146.26 1512.99,1146.26 1512.99,1148.03 1516.54,1151.57 1532.48,1151.57 1534.25,1149.8 1536.02,1149.8 1536.02,1148.03 1537.8,1148.03 1537.8,1146.26 1539.57,1146.26 1539.57,1144.49 1541.34,1144.49 1551.97,1133.86 1576.77,1133.86 RAD_U29.H16@1576.21,1134.44
  Top Layer w7.09: RAD_R264.1@1515.75,767.72 1514.76,767.72 1535.43,788.39 1576.77,788.39 1576.77,785.43 1579.72,782.48 1579.72,776.57 v5(1585.63,770.67) ; v2(2643.7,812.99) TP_RAD_RESET.1@2661.42,795.28
  GND1 w6.69: v10(2539.37,984.25) 2538.39,953.74 2541.34,918.31 v8(2566.93,889.76)
  SIG1 w6.3: v2(1399.61,1135.63) 1399.61,1029.33 1461.61,967.32 1461.61,924.8 1452.76,915.94 1452.76,864.57 1456.3,861.02 1456.3,843.31 1417.32,804.33 v2(1408.46,804.33)
  SIG1 w7.09: v5(1396.65,717.52) 1435.04,755.91 1559.06,755.91 1570.87,767.72 1582.68,767.72 v5(1585.63,770.67) ; v8(2566.93,889.76) 2588.58,889.76 2616.14,862.2 v2(2643.7,812.99)
  SIG2 w6.69: v5(1585.63,770.67) 1586.61,771.65 1614.17,771.65 1708.66,677.17 2055.12,677.17 2275.59,897.64 2559.06,897.64 v8(2566.93,889.76)
  Bottom Layer w6.3: v2(1408.46,804.33) 1420.87,791.93 1424.41,791.93 RAD_C105.2@1424.61,792.72
  Bottom Layer w7.09: v5(1396.65,717.52) 1417.32,738.19 1417.32,788.39 RAD_C105.2@1417.32,787.4
TI_AR_WRMRST: RAD_U29.B12
TI_BSS_UARTA_TX: RAD_U29.M16
TI_CANA_NSTB: RAD_R13.1
TI_CANB_NSTB: RAD_R17.1
TI_CSI2_RX0_0_N: RAD_U29.N18
TI_CSI2_RX0_0_P: RAD_U29.N17
TI_CSI2_RX0_1_N: RAD_U29.M18
TI_CSI2_RX0_1_P: RAD_U29.M17
TI_CSI2_RX0_CLK_N: RAD_U29.L18
TI_CSI2_RX0_CLK_P: RAD_U29.L17
TI_DSS_UARTA_RX: RAD_U29.B14
TI_DSS_UARTA_TX: RAD_U29.A15
TI_FB_B1: RAD_R14.1 RAD_U8.3 | length 547.5
  GND1 w6.69: v7(1791.34,866.14) 1792.13,925.98 1774.8,943.31 1774.8,974.8 1825.2,1025.2 1853.54,1025.2 1861.42,1022.05 1918.11,1022.05 2018.9,1122.83 2018.9,1133.86 2042.52,1157.48 2061.42,1157.48 2072.44,1146.46 v7(2083.17,1102.36)
TI_FB_B2: RAD_R71.1 RAD_U8.21 | length 927.3
  GND1 w6.69: v7@2245.67,1100.79 2286.61,1102.36 2300.79,1088.19 2300.79,1040.94 2324.41,1017.32 v2@2368.5,1017.32 ; v7(2247.54,1102.36) 2280.02,1102.36 2343.5,1088.58 2349.9,1083.66 2352.85,1078.25 v2(2373.03,1018.7)
  GND2 w6.69: v9@1949.61,691.34 2099.21,834.65 2222.05,834.65 2333.86,946.46 v2@2368.5,1017.32
  other v9: 1948.82,688.98
TI_FB_B3: RAD_R291.1 RAD_U8.17 | length 644.3
  GND2 w6.69: v9(1828.35,814.17) 1828.35,796.85 1856.69,768.5 1937.01,768.5 2009.45,840.94 2067.72,840.94 2144.88,918.11 2163.78,918.11 2184.25,938.58 v2(2247.54,1023.62)
  Bottom Layer w6.69: v9(1791.34,885.83) 1812.6,864.57 v9(1828.35,814.17)
TI_GPADC1: RAD_U29.P3
TI_GPADC2: RAD_U29.P2
TI_GPADC3: RAD_U29.R3
TI_GPADC4: RAD_U29.R2
TI_GPADC5: RAD_U29.T3
TI_GPADC6: RAD_U29.U2
TI_GPADC7: RAD_U29.T1
TI_GPADC8: RAD_U29.T2
TI_GPADC9: RAD_U29.U1
TI_GPIO_3: RAD_U29.P16
TI_GPIO_4: RAD_U29.L15
TI_GPIO_8: RAD_U29.T18
TI_GPIO_9: RAD_U29.N15
TI_GPIO_30: RAD_U29.P17
TI_GPIO_31: RAD_U29.U17
TI_LVDS_TX0_N: RAD_U29.F18
TI_LVDS_TX0_P: RAD_U29.F17
TI_LVDS_TX1_N: RAD_U29.J18
TI_LVDS_TX1_P: RAD_U29.J17
TI_LVDS_TX2_CLK_N: RAD_U29.G18
TI_LVDS_TX2_CLK_P: RAD_U29.G17
TI_LVDS_TX3_FRCLK_N: RAD_U29.H18
TI_LVDS_TX3_FRCLK_P: RAD_U29.H17
TI_MCU_CLK_OUT: RAD_U29.R15
TI_MSS_EPWMA0: RAD_U29.E15
TI_MSS_EPWMA1: RAD_U29.C18
TI_MSS_EPWMB0: RAD_U29.C17
TI_MSS_GPIO_0: RAD_U29.B15
TI_MSS_GPIO_1: RAD_U29.A16
TI_MSS_GPIO_11: RAD_U29.J15
TI_MSS_GPIO_28: RAD_U29.R17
